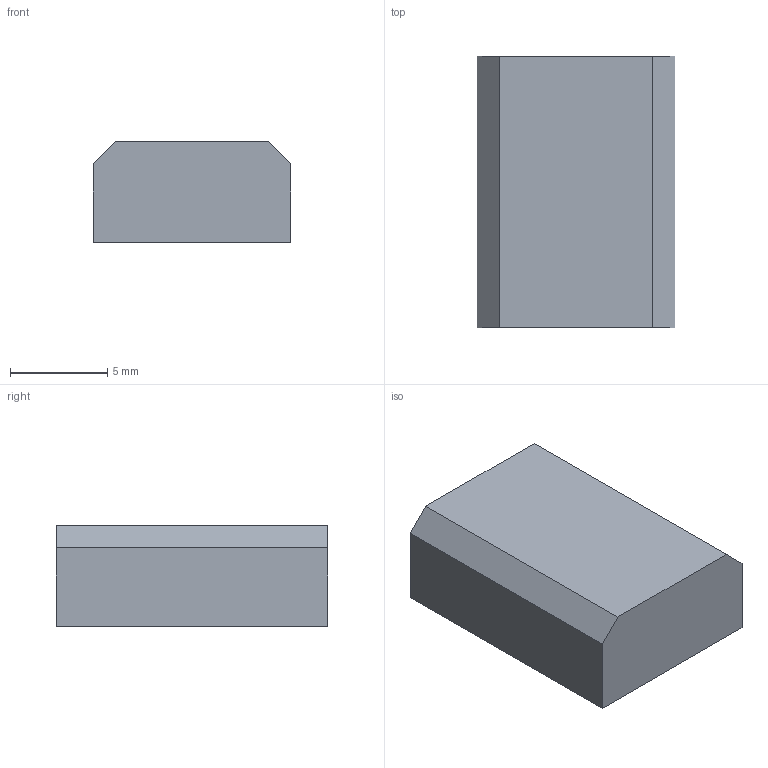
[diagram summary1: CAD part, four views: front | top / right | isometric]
STEP (ISO 10303-21) file: header records copied from the file, then geometry measured from it (millimetres).
FILE_DESCRIPTION(('Open CASCADE Model'),'2;1');
FILE_NAME('Open CASCADE Shape Model','2026-10-13T14:04:57',('Author'),( 'Open CASCADE'),'Open CASCADE STEP processor 8.0','build123d', 'Unknown');
FILE_SCHEMA(('AUTOMOTIVE_DESIGN { 1 0 10303 214 1 1 1 1 }'));
Length unit declared in the file: millimetre
Products named in the file (4): COMPOUND
Assembly tree (3 placements, depth 2):
  COMPOUND
    COMPOUND
    COMPOUND
    COMPOUND
Bounding box: 10.2 x 14 x 5.2 mm (x, y, z)
Volume: 597.6 mm3; surface area: 824 mm2
Topology: 3 solids, 3 shells, 18 faces, 30 edges, 20 vertices
Faces by surface type: plane 14, cylinder 4
Full cylindrical faces by diameter (mm): 2.02 x2, 3.672 x2
Entity records: 932 total; most frequent: CARTESIAN_POINT 144, DIRECTION 140, LINE 74, VECTOR 74, ORIENTED_EDGE 60, PCURVE 60, DEFINITIONAL_REPRESENTATION 60, AXIS2_PLACEMENT_3D 30
One B-rep face of a CAD part: STEP entity #590.
In plain terms, the planar face has unit normal (0, 0, 1).
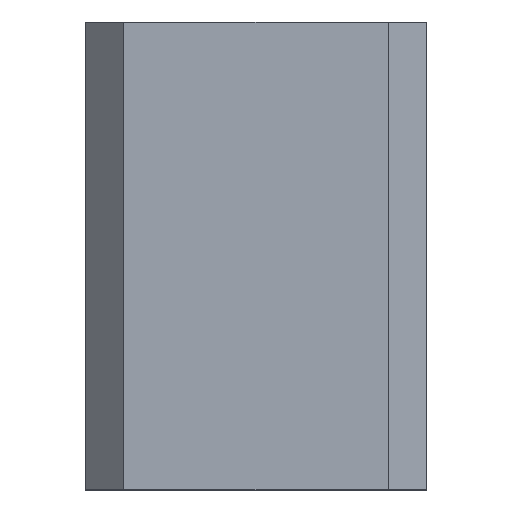
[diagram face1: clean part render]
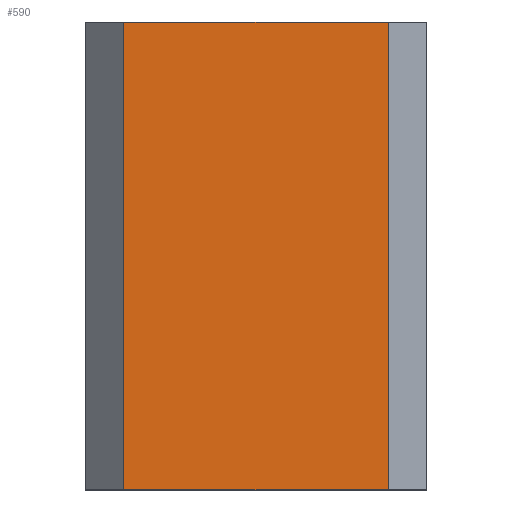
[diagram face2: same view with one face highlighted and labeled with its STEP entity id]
Its self-contained STEP definition (entity closure, numbers rounded to 3 decimals):
#70 = PLANE('',#71);
#71 = AXIS2_PLACEMENT_3D('',#72,#73,#74);
#72 = CARTESIAN_POINT('',(-7.6,0.4,0.));
#73 = DIRECTION('',(-0.,1.,0.));
#74 = DIRECTION('',(0.,0.,1.));
#126 = PLANE('',#127);
#127 = AXIS2_PLACEMENT_3D('',#128,#129,#130);
#128 = CARTESIAN_POINT('',(-7.6,14.4,0.));
#129 = DIRECTION('',(-0.,1.,0.));
#130 = DIRECTION('',(0.,0.,1.));
#152 = PLANE('',#153);
#153 = AXIS2_PLACEMENT_3D('',#154,#155,#156);
#154 = CARTESIAN_POINT('',(-7.028,0.4,4.628));
#155 = DIRECTION('',(0.707,0.,-0.707));
#156 = DIRECTION('',(0.,1.,0.));
#220 = VERTEX_POINT('',#221);
#221 = CARTESIAN_POINT('',(-6.456,0.4,5.2));
#242 = EDGE_CURVE('',#220,#243,#245,.T.);
#243 = VERTEX_POINT('',#244);
#244 = CARTESIAN_POINT('',(1.456,0.4,5.2));
#245 = SURFACE_CURVE('',#246,(#250,#257),.PCURVE_S1.);
#246 = LINE('',#247,#248);
#247 = CARTESIAN_POINT('',(-7.6,0.4,5.2));
#248 = VECTOR('',#249,1.);
#249 = DIRECTION('',(1.,0.,-0.));
#250 = PCURVE('',#70,#251);
#251 = DEFINITIONAL_REPRESENTATION('',(#252),#256);
#252 = LINE('',#253,#254);
#253 = CARTESIAN_POINT('',(5.2,0.));
#254 = VECTOR('',#255,1.);
#255 = DIRECTION('',(0.,1.));
#256 = ( GEOMETRIC_REPRESENTATION_CONTEXT(2) 
PARAMETRIC_REPRESENTATION_CONTEXT() REPRESENTATION_CONTEXT('2D SPACE',''
  ) );
#257 = PCURVE('',#258,#263);
#258 = PLANE('',#259);
#259 = AXIS2_PLACEMENT_3D('',#260,#261,#262);
#260 = CARTESIAN_POINT('',(-7.6,0.4,5.2));
#261 = DIRECTION('',(0.,0.,1.));
#262 = DIRECTION('',(1.,0.,-0.));
#263 = DEFINITIONAL_REPRESENTATION('',(#264),#268);
#264 = LINE('',#265,#266);
#265 = CARTESIAN_POINT('',(0.,0.));
#266 = VECTOR('',#267,1.);
#267 = DIRECTION('',(1.,0.));
#268 = ( GEOMETRIC_REPRESENTATION_CONTEXT(2) 
PARAMETRIC_REPRESENTATION_CONTEXT() REPRESENTATION_CONTEXT('2D SPACE',''
  ) );
#284 = PLANE('',#285);
#285 = AXIS2_PLACEMENT_3D('',#286,#287,#288);
#286 = CARTESIAN_POINT('',(2.028,0.4,4.628));
#287 = DIRECTION('',(0.707,0.,0.707));
#288 = DIRECTION('',(-0.,1.,0.));
#302 = VERTEX_POINT('',#303);
#303 = CARTESIAN_POINT('',(-6.456,14.4,5.2));
#324 = EDGE_CURVE('',#220,#302,#325,.T.);
#325 = SURFACE_CURVE('',#326,(#330,#337),.PCURVE_S1.);
#326 = LINE('',#327,#328);
#327 = CARTESIAN_POINT('',(-6.456,0.4,5.2));
#328 = VECTOR('',#329,1.);
#329 = DIRECTION('',(-0.,1.,0.));
#330 = PCURVE('',#152,#331);
#331 = DEFINITIONAL_REPRESENTATION('',(#332),#336);
#332 = LINE('',#333,#334);
#333 = CARTESIAN_POINT('',(0.,0.809));
#334 = VECTOR('',#335,1.);
#335 = DIRECTION('',(1.,0.));
#336 = ( GEOMETRIC_REPRESENTATION_CONTEXT(2) 
PARAMETRIC_REPRESENTATION_CONTEXT() REPRESENTATION_CONTEXT('2D SPACE',''
  ) );
#337 = PCURVE('',#258,#338);
#338 = DEFINITIONAL_REPRESENTATION('',(#339),#343);
#339 = LINE('',#340,#341);
#340 = CARTESIAN_POINT('',(1.144,0.));
#341 = VECTOR('',#342,1.);
#342 = DIRECTION('',(0.,1.));
#343 = ( GEOMETRIC_REPRESENTATION_CONTEXT(2) 
PARAMETRIC_REPRESENTATION_CONTEXT() REPRESENTATION_CONTEXT('2D SPACE',''
  ) );
#423 = EDGE_CURVE('',#302,#424,#426,.T.);
#424 = VERTEX_POINT('',#425);
#425 = CARTESIAN_POINT('',(1.456,14.4,5.2));
#426 = SURFACE_CURVE('',#427,(#431,#438),.PCURVE_S1.);
#427 = LINE('',#428,#429);
#428 = CARTESIAN_POINT('',(-7.6,14.4,5.2));
#429 = VECTOR('',#430,1.);
#430 = DIRECTION('',(1.,0.,-0.));
#431 = PCURVE('',#126,#432);
#432 = DEFINITIONAL_REPRESENTATION('',(#433),#437);
#433 = LINE('',#434,#435);
#434 = CARTESIAN_POINT('',(5.2,0.));
#435 = VECTOR('',#436,1.);
#436 = DIRECTION('',(0.,1.));
#437 = ( GEOMETRIC_REPRESENTATION_CONTEXT(2) 
PARAMETRIC_REPRESENTATION_CONTEXT() REPRESENTATION_CONTEXT('2D SPACE',''
  ) );
#438 = PCURVE('',#258,#439);
#439 = DEFINITIONAL_REPRESENTATION('',(#440),#444);
#440 = LINE('',#441,#442);
#441 = CARTESIAN_POINT('',(0.,14.));
#442 = VECTOR('',#443,1.);
#443 = DIRECTION('',(1.,0.));
#444 = ( GEOMETRIC_REPRESENTATION_CONTEXT(2) 
PARAMETRIC_REPRESENTATION_CONTEXT() REPRESENTATION_CONTEXT('2D SPACE',''
  ) );
#570 = EDGE_CURVE('',#243,#424,#571,.T.);
#571 = SURFACE_CURVE('',#572,(#576,#583),.PCURVE_S1.);
#572 = LINE('',#573,#574);
#573 = CARTESIAN_POINT('',(1.456,0.4,5.2));
#574 = VECTOR('',#575,1.);
#575 = DIRECTION('',(-0.,1.,0.));
#576 = PCURVE('',#284,#577);
#577 = DEFINITIONAL_REPRESENTATION('',(#578),#582);
#578 = LINE('',#579,#580);
#579 = CARTESIAN_POINT('',(0.,0.809));
#580 = VECTOR('',#581,1.);
#581 = DIRECTION('',(1.,0.));
#582 = ( GEOMETRIC_REPRESENTATION_CONTEXT(2) 
PARAMETRIC_REPRESENTATION_CONTEXT() REPRESENTATION_CONTEXT('2D SPACE',''
  ) );
#583 = PCURVE('',#258,#584);
#584 = DEFINITIONAL_REPRESENTATION('',(#585),#589);
#585 = LINE('',#586,#587);
#586 = CARTESIAN_POINT('',(9.056,0.));
#587 = VECTOR('',#588,1.);
#588 = DIRECTION('',(0.,1.));
#589 = ( GEOMETRIC_REPRESENTATION_CONTEXT(2) 
PARAMETRIC_REPRESENTATION_CONTEXT() REPRESENTATION_CONTEXT('2D SPACE',''
  ) );
#590 = ADVANCED_FACE('',(#591),#258,.T.);
#591 = FACE_BOUND('',#592,.T.);
#592 = EDGE_LOOP('',(#593,#594,#595,#596));
#593 = ORIENTED_EDGE('',*,*,#423,.F.);
#594 = ORIENTED_EDGE('',*,*,#324,.F.);
#595 = ORIENTED_EDGE('',*,*,#242,.T.);
#596 = ORIENTED_EDGE('',*,*,#570,.T.);
